VERSION 5.8 ;
BUSBITCHARS "[]" ;
DIVIDERCHAR "/" ;

PROPERTYDEFINITIONS
  MACRO SDLpower STRING ;
  MACRO SDLground STRING ;
  MACRO SDLglobal STRING ;
END PROPERTYDEFINITIONS

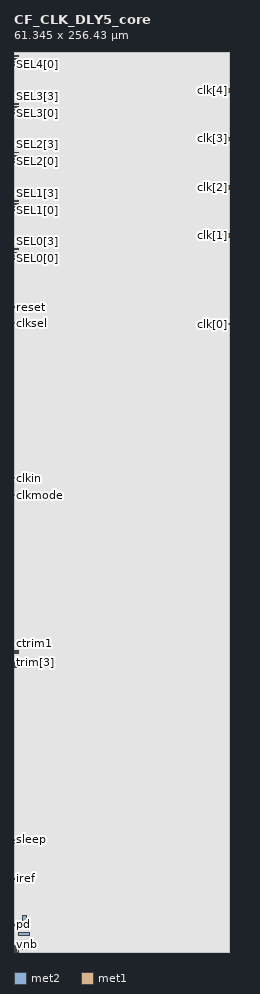
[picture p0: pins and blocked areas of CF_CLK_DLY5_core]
MACRO CF_CLK_DLY5_core
  ORIGIN 0 0 ;
  FOREIGN CF_CLK_DLY5_core 0 0 ;
  SIZE 61.345 BY 256.43 ;
  PIN vpwri
    DIRECTION OUTPUT ;
    USE SIGNAL ;
    PORT
      LAYER met2 ;
        RECT 1.28 4.6 4.3 5.6 ;
    END
  END vpwri
  PIN sleep
    DIRECTION INPUT ;
    USE SIGNAL ;
    PORT
      LAYER met1 ;
        RECT 0 31.795 1.14 32.085 ;
    END
  END sleep
  PIN SEL0[0]
    DIRECTION INPUT ;
    USE SIGNAL ;
    PORT
      LAYER met1 ;
        RECT 0 197.41 1.14 197.67 ;
    END
  END SEL0[0]
  PIN SEL4[0]
    DIRECTION INPUT ;
    USE SIGNAL ;
    PORT
      LAYER met1 ;
        RECT 0 252.65 1.14 252.91 ;
    END
  END SEL4[0]
  PIN SEL4[2]
    DIRECTION INPUT ;
    USE SIGNAL ;
    PORT
      LAYER met1 ;
        RECT 0 254.41 1.14 254.67 ;
    END
  END SEL4[2]
  PIN SEL4[1]
    DIRECTION INPUT ;
    USE SIGNAL ;
    PORT
      LAYER met1 ;
        RECT 0 253.53 1.14 253.79 ;
    END
  END SEL4[1]
  PIN SEL3[3]
    DIRECTION INPUT ;
    USE SIGNAL ;
    PORT
      LAYER met1 ;
        RECT 0 241.48 1.14 241.74 ;
    END
  END SEL3[3]
  PIN SEL3[2]
    DIRECTION INPUT ;
    USE SIGNAL ;
    PORT
      LAYER met1 ;
        RECT 0 240.6 1.14 240.86 ;
    END
  END SEL3[2]
  PIN SEL3[1]
    DIRECTION INPUT ;
    USE SIGNAL ;
    PORT
      LAYER met1 ;
        RECT 0 239.72 1.14 239.98 ;
    END
  END SEL3[1]
  PIN SEL3[0]
    DIRECTION INPUT ;
    USE SIGNAL ;
    PORT
      LAYER met1 ;
        RECT 0 238.84 1.14 239.1 ;
    END
  END SEL3[0]
  PIN SEL2[3]
    DIRECTION INPUT ;
    USE SIGNAL ;
    PORT
      LAYER met1 ;
        RECT 0 227.67 1.14 227.93 ;
    END
  END SEL2[3]
  PIN SEL2[2]
    DIRECTION INPUT ;
    USE SIGNAL ;
    PORT
      LAYER met1 ;
        RECT 0 226.79 1.14 227.05 ;
    END
  END SEL2[2]
  PIN SEL2[1]
    DIRECTION INPUT ;
    USE SIGNAL ;
    PORT
      LAYER met1 ;
        RECT 0 225.91 1.14 226.17 ;
    END
  END SEL2[1]
  PIN SEL2[0]
    DIRECTION INPUT ;
    USE SIGNAL ;
    PORT
      LAYER met1 ;
        RECT 0 225.03 1.14 225.29 ;
    END
  END SEL2[0]
  PIN SEL0[1]
    DIRECTION INPUT ;
    USE SIGNAL ;
    PORT
      LAYER met1 ;
        RECT 0 198.29 1.14 198.55 ;
    END
  END SEL0[1]
  PIN SEL1[3]
    DIRECTION INPUT ;
    USE SIGNAL ;
    PORT
      LAYER met1 ;
        RECT 0 213.86 1.14 214.12 ;
    END
  END SEL1[3]
  PIN SEL1[2]
    DIRECTION INPUT ;
    USE SIGNAL ;
    PORT
      LAYER met1 ;
        RECT 0 212.98 1.14 213.24 ;
    END
  END SEL1[2]
  PIN SEL1[1]
    DIRECTION INPUT ;
    USE SIGNAL ;
    PORT
      LAYER met1 ;
        RECT 0 212.1 1.14 212.36 ;
    END
  END SEL1[1]
  PIN SEL1[0]
    DIRECTION INPUT ;
    USE SIGNAL ;
    PORT
      LAYER met1 ;
        RECT 0 211.22 1.14 211.48 ;
    END
  END SEL1[0]
  PIN SEL0[3]
    DIRECTION INPUT ;
    USE SIGNAL ;
    PORT
      LAYER met1 ;
        RECT 0 200.05 1.14 200.31 ;
    END
  END SEL0[3]
  PIN SEL0[2]
    DIRECTION INPUT ;
    USE SIGNAL ;
    PORT
      LAYER met1 ;
        RECT 0 199.17 1.14 199.43 ;
    END
  END SEL0[2]
  PIN clkmode
    DIRECTION INPUT ;
    USE SIGNAL ;
    PORT
      LAYER met1 ;
        RECT 0.005 130.05 1.14 130.34 ;
    END
  END clkmode
  PIN clkin
    DIRECTION INPUT ;
    USE SIGNAL ;
    PORT
      LAYER met1 ;
        RECT 0 134.86 1.14 135.15 ;
    END
  END clkin
  PIN SEL4[3]
    DIRECTION INPUT ;
    USE SIGNAL ;
    PORT
      LAYER met1 ;
        RECT 0 255.29 1.14 255.55 ;
    END
  END SEL4[3]
  PIN ctrim0
    DIRECTION INPUT ;
    USE SIGNAL ;
    PORT
      LAYER met1 ;
        RECT 0 84.955 1.14 85.245 ;
    END
  END ctrim0
  PIN clksel
    DIRECTION INPUT ;
    USE SIGNAL ;
    PORT
      LAYER met1 ;
        RECT 0 179.03 1.14 179.32 ;
    END
  END clksel
  PIN trim[2]
    DIRECTION INPUT ;
    USE SIGNAL ;
    PORT
      LAYER met1 ;
        RECT 0 81.985 1.14 82.275 ;
    END
  END trim[2]
  PIN trim[1]
    DIRECTION INPUT ;
    USE SIGNAL ;
    PORT
      LAYER met1 ;
        RECT 0 81.555 1.14 81.845 ;
    END
  END trim[1]
  PIN trim[0]
    DIRECTION INPUT ;
    USE SIGNAL ;
    PORT
      LAYER met1 ;
        RECT 0 81.125 1.14 81.415 ;
    END
  END trim[0]
  PIN reset
    DIRECTION INPUT ;
    USE SIGNAL ;
    PORT
      LAYER met1 ;
        RECT 0 183.5 1.14 183.79 ;
    END
  END reset
  PIN pd
    DIRECTION INPUT ;
    USE SIGNAL ;
    PORT
      LAYER met1 ;
        RECT 0 7.6 1.14 7.89 ;
    END
  END pd
  PIN isel
    DIRECTION INPUT ;
    USE SIGNAL ;
    PORT
      LAYER met1 ;
        RECT 0 31.005 1.14 31.295 ;
    END
  END isel
  PIN iref
    DIRECTION INPUT ;
    USE SIGNAL ;
    PORT
      LAYER met1 ;
        RECT 0 20.725 1.14 21.015 ;
    END
  END iref
  PIN ctrim1
    DIRECTION INPUT ;
    USE SIGNAL ;
    PORT
      LAYER met1 ;
        RECT 0 85.495 1.14 85.785 ;
    END
  END ctrim1
  PIN trim[3]
    DIRECTION INPUT ;
    USE SIGNAL ;
    PORT
      LAYER met1 ;
        RECT 0 82.415 1.14 82.7 ;
    END
  END trim[3]
  PIN trim[4]
    DIRECTION INPUT ;
    USE SIGNAL ;
    PORT
      LAYER met1 ;
        RECT 0 82.845 1.14 83.135 ;
    END
  END trim[4]
  PIN vgnd
    DIRECTION INPUT ;
    USE SIGNAL ;
    PORT
      LAYER met2 ;
        RECT 2.42 8.39 3.42 10.395 ;
    END
  END vgnd
  PIN vnb
    DIRECTION INPUT ;
    USE SIGNAL ;
    PORT
      LAYER met2 ;
        RECT 0.64 0 1.14 1.72 ;
    END
  END vnb
  PIN vpb
    DIRECTION INPUT ;
    USE SIGNAL ;
    PORT
      LAYER met2 ;
        RECT 0 0 0.5 1.72 ;
    END
  END vpb
  PIN vpwr
    DIRECTION INPUT ;
    USE SIGNAL ;
    PORT
      LAYER met2 ;
        RECT 2.51 0.61 5.575 1.61 ;
    END
  END vpwr
  PIN clk[0]
    DIRECTION OUTPUT ;
    USE SIGNAL ;
    PORT
      LAYER met1 ;
        RECT 60.46 178.755 61.345 178.985 ;
    END
  END clk[0]
  PIN clk[1]
    DIRECTION OUTPUT ;
    USE SIGNAL ;
    PORT
      LAYER met1 ;
        RECT 60.46 203.53 61.345 204.575 ;
    END
  END clk[1]
  PIN clk[2]
    DIRECTION OUTPUT ;
    USE SIGNAL ;
    PORT
      LAYER met1 ;
        RECT 60.46 217.34 61.345 218.385 ;
    END
  END clk[2]
  PIN clk[3]
    DIRECTION OUTPUT ;
    USE SIGNAL ;
    PORT
      LAYER met1 ;
        RECT 60.46 231.15 61.345 232.195 ;
    END
  END clk[3]
  PIN clk[4]
    DIRECTION OUTPUT ;
    USE SIGNAL ;
    PORT
      LAYER met1 ;
        RECT 60.46 244.96 61.345 246.005 ;
    END
  END clk[4]
  PROPERTY SDLpower "vpwr" ;
  PROPERTY SDLground "vgnd" ;
  PROPERTY SDLglobal "" ;
  OBS
    LAYER li1 ;
      RECT 0 0 61.345 256.43 ;
    LAYER met1 ;
      RECT 0 0 0.005 7.6 ;
      RECT 0 7.89 0.005 20.725 ;
      RECT 0 21.015 0.005 31.005 ;
      RECT 0 31.295 0.005 31.795 ;
      RECT 0 32.085 0.005 81.125 ;
      RECT 0 81.415 0.005 81.555 ;
      RECT 0 81.845 0.005 81.985 ;
      RECT 0 82.275 0.005 82.415 ;
      RECT 0 82.7 0.005 82.845 ;
      RECT 0 83.135 0.005 84.955 ;
      RECT 0 85.245 0.005 85.495 ;
      RECT 0 85.785 0.005 134.86 ;
      RECT 0 135.15 0.005 179.03 ;
      RECT 0 179.32 0.005 183.5 ;
      RECT 0 183.79 0.005 197.41 ;
      RECT 0 197.67 0.005 198.29 ;
      RECT 0 198.55 0.005 199.17 ;
      RECT 0 199.43 0.005 200.05 ;
      RECT 0 200.31 0.005 211.22 ;
      RECT 0 211.48 0.005 212.1 ;
      RECT 0 212.36 0.005 212.98 ;
      RECT 0 213.24 0.005 213.86 ;
      RECT 0 214.12 0.005 225.03 ;
      RECT 0 225.29 0.005 225.91 ;
      RECT 0 226.17 0.005 226.79 ;
      RECT 0 227.05 0.005 227.67 ;
      RECT 0 227.93 0.005 238.84 ;
      RECT 0 239.1 0.005 239.72 ;
      RECT 0 239.98 0.005 240.6 ;
      RECT 0 240.86 0.005 241.48 ;
      RECT 0 241.74 0.005 252.65 ;
      RECT 0 252.91 0.005 253.53 ;
      RECT 0 253.79 0.005 254.41 ;
      RECT 0 254.67 0.005 255.29 ;
      RECT 0 255.55 0.005 256.43 ;
      RECT 0.005 0 1.14 7.6 ;
      RECT 0.005 7.89 1.14 20.725 ;
      RECT 0.005 21.015 1.14 31.005 ;
      RECT 0.005 31.295 1.14 31.795 ;
      RECT 0.005 32.085 1.14 81.125 ;
      RECT 0.005 81.415 1.14 81.555 ;
      RECT 0.005 81.845 1.14 81.985 ;
      RECT 0.005 82.275 1.14 82.415 ;
      RECT 0.005 82.7 1.14 82.845 ;
      RECT 0.005 83.135 1.14 84.955 ;
      RECT 0.005 85.245 1.14 85.495 ;
      RECT 0.005 85.785 1.14 130.05 ;
      RECT 0.005 130.34 1.14 134.86 ;
      RECT 0.005 135.15 1.14 179.03 ;
      RECT 0.005 179.32 1.14 183.5 ;
      RECT 0.005 183.79 1.14 197.41 ;
      RECT 0.005 197.67 1.14 198.29 ;
      RECT 0.005 198.55 1.14 199.17 ;
      RECT 0.005 199.43 1.14 200.05 ;
      RECT 0.005 200.31 1.14 211.22 ;
      RECT 0.005 211.48 1.14 212.1 ;
      RECT 0.005 212.36 1.14 212.98 ;
      RECT 0.005 213.24 1.14 213.86 ;
      RECT 0.005 214.12 1.14 225.03 ;
      RECT 0.005 225.29 1.14 225.91 ;
      RECT 0.005 226.17 1.14 226.79 ;
      RECT 0.005 227.05 1.14 227.67 ;
      RECT 0.005 227.93 1.14 238.84 ;
      RECT 0.005 239.1 1.14 239.72 ;
      RECT 0.005 239.98 1.14 240.6 ;
      RECT 0.005 240.86 1.14 241.48 ;
      RECT 0.005 241.74 1.14 252.65 ;
      RECT 0.005 252.91 1.14 253.53 ;
      RECT 0.005 253.79 1.14 254.41 ;
      RECT 0.005 254.67 1.14 255.29 ;
      RECT 0.005 255.55 1.14 256.43 ;
      RECT 1.14 0 60.46 256.43 ;
      RECT 60.46 0 61.345 178.755 ;
      RECT 60.46 178.985 61.345 203.53 ;
      RECT 60.46 204.575 61.345 217.34 ;
      RECT 60.46 218.385 61.345 231.15 ;
      RECT 60.46 232.195 61.345 244.96 ;
      RECT 60.46 246.005 61.345 256.43 ;
    LAYER met2 ;
      RECT 0 1.72 0.5 256.43 ;
      RECT 0.5 0 0.64 256.43 ;
      RECT 0.64 1.72 1.14 256.43 ;
      RECT 1.14 0 1.28 256.43 ;
      RECT 1.28 0 2.42 4.6 ;
      RECT 1.28 5.6 2.42 256.43 ;
      RECT 2.42 0 2.51 4.6 ;
      RECT 2.42 5.6 2.51 8.39 ;
      RECT 2.42 10.395 2.51 256.43 ;
      RECT 2.51 0 3.42 0.61 ;
      RECT 2.51 1.61 3.42 4.6 ;
      RECT 2.51 5.6 3.42 8.39 ;
      RECT 2.51 10.395 3.42 256.43 ;
      RECT 3.42 0 4.3 0.61 ;
      RECT 3.42 1.61 4.3 4.6 ;
      RECT 3.42 5.6 4.3 256.43 ;
      RECT 4.3 0 5.575 0.61 ;
      RECT 4.3 1.61 5.575 256.43 ;
      RECT 5.575 0 61.345 256.43 ;
    LAYER met3 ;
      RECT 0 0 61.345 256.43 ;
  END
END CF_CLK_DLY5_core

END LIBRARY
